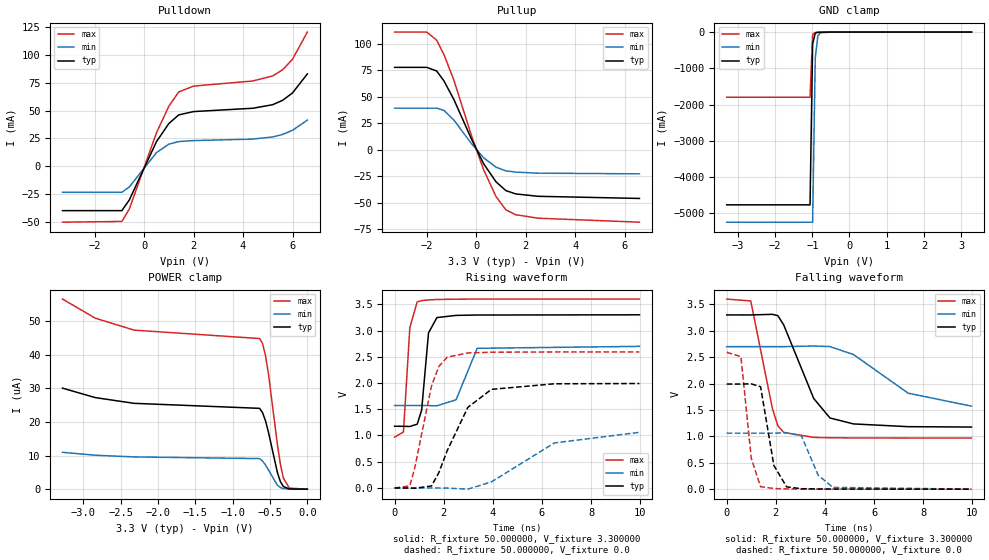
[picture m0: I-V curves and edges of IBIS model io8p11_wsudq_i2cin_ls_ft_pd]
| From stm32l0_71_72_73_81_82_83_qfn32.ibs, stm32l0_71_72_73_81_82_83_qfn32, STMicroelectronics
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|   Model io8p11_wsudq_i2cin_ls_ft_pd
[Model]  io8p11_wsudq_i2cin_ls_ft_pd
Model_type I/O
Polarity   Non-Inverting
Enable   Active-Low
Vinl =   0.990000V
Vinh =   2.310000V
Vmeas =  1.650000V
Cref =   50.000000pF
Rref =   100.000000M
Vref =   0.0V
C_comp   3.020400pF   2.988300pF   3.054500pF
[Temperature Range]   25.000000   0.125000k   -40.000000
[Pullup Reference]   3.300000V   2.700000V   3.600000V
[Pulldown Reference]   0.0V   0.0V   0.0V
[POWER Clamp Reference]   3.300000V   2.700000V   3.600000V
[GND Clamp Reference]   0.0V   0.0V   0.0V
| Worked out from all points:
|   slope of the pulldown table from 0 to 0.495 V, typ, clamps not added: 22.6 ohm
|   slope of the pullup table from 0 to 0.495 V, typ, clamps not added: 23.9 ohm
|   GND clamp passes 1 mA (typ) near -0.64 V on its own axis
|   rising waveform, R_fixture 50.000000, V_fixture 3.300000: 20-80 % time 225ps typ, 371ps min, 186ps max; typ from 1.18 V to 3.3 V
|   rising waveform, R_fixture 50.000000, V_fixture 0.0: 20-80 % time 1.18ns typ, 2.2ns min, 710ps max; typ from 0 V to 1.99 V
|   falling waveform, R_fixture 50.000000, V_fixture 3.300000: 20-80 % time 1.13ns typ, 2.09ns min, 655ps max; typ from 3.3 V to 1.18 V
|   falling waveform, R_fixture 50.000000, V_fixture 0.0: 20-80 % time 408ps typ, 574ps min, 329ps max; typ from 1.99 V to 0 V
[Pulldown]
|Voltage   I(typ)   I(min)   I(max)
-3.3V     -39.83mA   -23.37mA   -50.2mA
-900mV    -39.83mA   -23.37mA   -49.53mA
-600mV    -30.28mA   -18.59mA   -38.45mA
500mV     22.11mA    12.28mA    30.1mA
1V        38.33mA    19.81mA    53.88mA
1.4V      46.1mA     22.18mA    66.72mA
2V        49.07mA    23.02mA    71.93mA
4.4V      52.05mA    24.38mA    76.53mA
5.2V      55.25mA    26.3mA     81.02mA
5.6V      59.18mA    28.57mA    86.57mA
6V        65.79mA    32.24mA    95.97mA
6.6V      82.83mA    41.41mA    120.4mA
[Pullup]
|Voltage   I(typ)   I(min)   I(max)
-3.3V     77.63mA    39.16mA    110.9mA
-2V       77.63mA    39.16mA    110.9mA
-1.6V     74.23mA    39.16mA    103.3mA
-1.3V     64.67mA    36.99mA    89.45mA
-900mV    47.14mA    27.82mA    65.37mA
-200mV    10.4mA     5.949mA    13.84mA
300mV     -13.29mA   -7.65mA    -18.99mA
800mV     -30.32mA   -16.54mA   -44.19mA
1.2V      -38.62mA   -20mA      -56.79mA
1.6V      -41.75mA   -21.17mA   -61.39mA
2.5V      -43.99mA   -22.16mA   -64.64mA
6.6V      -46.01mA   -22.8mA    -68.41mA
[GND_clamp]
|Voltage   I(typ)   I(min)   I(max)
-3.3V     -4.766A    -5.244A    -1.797A
-1.06V    -4.766A    -5.244A    -1.797A
-990mV    -326.6mA   -5.244A    -67.91mA
-920mV    -28.93mA   -722.1mA   -10.97mA
-850mV    -6.625mA   -104.2mA   -6.541mA
-780mV    -3.477mA   -17.29mA   -4.218mA
-500mV    -68.5uA    -183uA     -41.48uA
3.28V     73.94uA    88.61uA    51.47uA
[POWER_clamp]
|Voltage   I(typ)   I(min)   I(max)
-3.28V    30.07uA    10.97uA    56.59uA
-2.84V    27.25uA    10.1uA     50.89uA
-2.32V    25.55uA    9.602uA    47.34uA
-640mV    24.06uA    9.099uA    44.84uA
-600mV    22.76uA    8.364uA    43.37uA
-560mV    20.32uA    7.211uA    39.74uA
-520mV    16.86uA    5.675uA    34.14uA
-400mV    4.841uA    1.145uA    13.1uA
-360mV    2.184uA    477.2nA    7.288uA
-320mV    772.4nA    180.3nA    3.213uA
-240mV    60.03nA    0A         295.3nA
0V        0A         0A         0A
[Ramp]
| variable   typ   min   max
dV/dt_r  1.19310/1.18050n   0.60954/2.07925n   1.55490/0.70842n
dV/dt_f  1.27158/1.13158n   0.59274/1.87936n   1.57816/0.65341n
R_load = 50.000000
[Rising Waveform]
R_fixture= 50.000000
V_fixture= 3.300000
V_fixture_min= 2.700000
V_fixture_max= 3.600000
|time   V(typ)   V(min)   V(max)
0s        1.176V     1.571V     967.8mV
360.4ps   1.175V     1.571V     1.067V
620.6ps   1.172V     1.571V     3.055V
920.9ps   1.216V     1.571V     3.545V
1.101ns   1.483V     1.571V     3.569V
1.381ns   2.954V     1.57V      3.583V
1.722ns   3.246V     1.566V     3.591V
2.503ns   3.288V     1.68V      3.597V
3.363ns   3.295V     2.661V     3.599V
9.97ns    3.299V     2.698V     3.599V
[Rising Waveform]
R_fixture= 50.000000
V_fixture= 0.0
V_fixture_min= 0.0
V_fixture_max= 0.0
|time   V(typ)   V(min)   V(max)
0s        -3.193uV   7.716uV    -219.6uV
620.6ps   -716.9uV   -7.893uV   40.33mV
820.8ps   -5.1mV     3.314uV    384.7mV
1.502ns   38.11mV    180.4uV    1.942V
1.802ns   292.1mV    -174uV     2.315V
2.142ns   711.3mV    -2.422mV   2.492V
2.983ns   1.536V     -22.39mV   2.573V
3.944ns   1.879V     116.5mV    2.587V
6.507ns   1.985V     857.8mV    2.591V
9.97ns    1.99V      1.06V      2.592V
[Falling Waveform]
R_fixture= 50.000000
V_fixture= 3.300000
V_fixture_min= 2.700000
V_fixture_max= 3.600000
|time   V(typ)   V(min)   V(max)
0s        3.299V     2.698V     3.599V
981ps     3.298V     2.698V     3.563V
1.862ns   3.31V      2.698V     1.525V
2.082ns   3.286V     2.698V     1.201V
2.322ns   3.11V      2.698V     1.074V
3.544ns   1.717V     2.71V      980.2mV
4.204ns   1.348V     2.699V     973.3mV
5.165ns   1.235V     2.549V     969.9mV
7.387ns   1.183V     1.818V     968.2mV
9.97ns    1.176V     1.571V     967.8mV
[Falling Waveform]
R_fixture= 50.000000
V_fixture= 0.0
V_fixture_min= 0.0
V_fixture_max= 0.0
|time   V(typ)   V(min)   V(max)
0s        1.99V      1.06V      2.592V
580.6ps   1.99V      1.06V      2.509V
1.001ns   1.994V     1.06V      584.3mV
1.381ns   1.938V     1.06V      46.33mV
1.922ns   448.1mV    1.06V      11.83mV
2.442ns   43.17mV    1.066V     4.743mV
3.043ns   8.498mV    1.01V      1.988mV
3.724ns   3.568mV    265.6mV    1.013mV
4.324ns   2.138mV    33.59mV    559.6uV
9.97ns    -3.193uV   7.716uV    -219.6uV
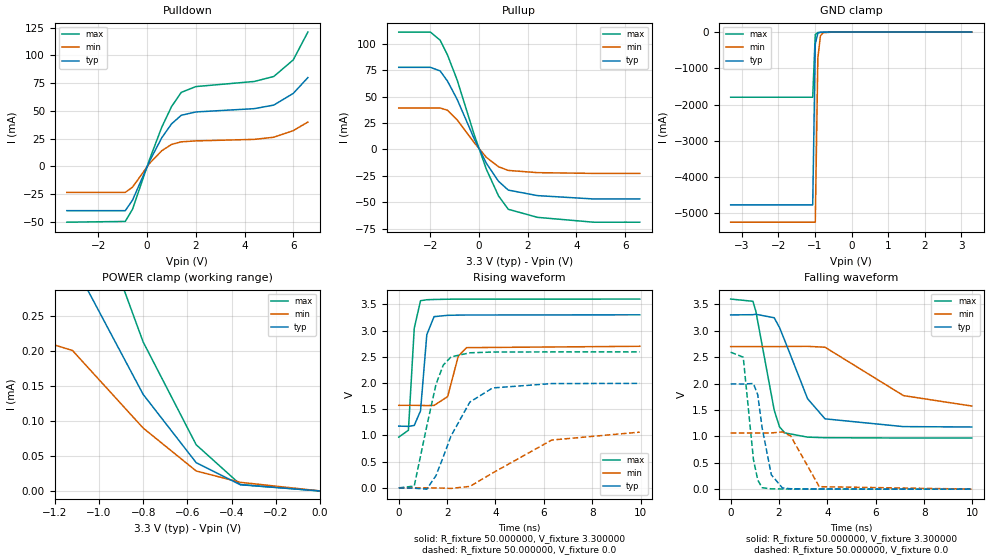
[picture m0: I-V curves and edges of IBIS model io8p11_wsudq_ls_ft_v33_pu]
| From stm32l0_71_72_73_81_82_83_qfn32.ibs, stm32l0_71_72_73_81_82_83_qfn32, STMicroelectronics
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|   Model io8p11_wsudq_ls_ft_v33_pu
[Model]  io8p11_wsudq_ls_ft_v33_pu
Model_type I/O
Polarity   Non-Inverting
Enable   Active-Low
Vinl =   0.990000V
Vinh =   2.310000V
Vmeas =  1.650000V
Cref =   50.000000pF
Rref =   100.000000M
Vref =   0.0V
C_comp   2.653200pF   2.620200pF   2.695100pF
[Temperature Range]   25.000000   0.125000k   -40.000000
[Pullup Reference]   3.300000V   2.700000V   3.600000V
[Pulldown Reference]   0.0V   0.0V   0.0V
[POWER Clamp Reference]   3.300000V   2.700000V   3.600000V
[GND Clamp Reference]   0.0V   0.0V   0.0V
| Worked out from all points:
|   slope of the pulldown table from 0 to 0.495 V, typ, clamps not added: 22.6 ohm
|   slope of the pullup table from 0 to 0.495 V, typ, clamps not added: 23.9 ohm
|   GND clamp passes 1 mA (typ) near -0.64 V on its own axis
|   POWER clamp passes 1 mA (typ) near -2.97 V on its own axis
|   rising waveform, R_fixture 50.000000, V_fixture 3.300000: 20-80 % time 215ps typ, 361ps min, 179ps max; typ from 1.18 V to 3.3 V
|   rising waveform, R_fixture 50.000000, V_fixture 0.0: 20-80 % time 1.18ns typ, 2.22ns min, 704ps max; typ from 0.001 V to 1.99 V
|   falling waveform, R_fixture 50.000000, V_fixture 3.300000: 20-80 % time 1.13ns typ, 2.11ns min, 645ps max; typ from 3.3 V to 1.18 V
|   falling waveform, R_fixture 50.000000, V_fixture 0.0: 20-80 % time 407ps typ, 577ps min, 327ps max; typ from 1.99 V to 0.001 V
[Pulldown]
|Voltage   I(typ)   I(min)   I(max)
-3.3V     -39.83mA   -23.37mA   -50.2mA
-900mV    -39.83mA   -23.37mA   -49.52mA
-600mV    -30.28mA   -18.59mA   -38.45mA
100mV     4.867mA    2.821mA    6.48mA
600mV     25.85mA    14.17mA    35.39mA
1V        38.33mA    19.81mA    53.88mA
1.4V      46.1mA     22.18mA    66.72mA
2V        49.07mA    23.02mA    71.93mA
4.4V      52.05mA    24.38mA    76.53mA
5.2V      55.25mA    26.31mA    81.02mA
6V        65.78mA    32.24mA    95.96mA
6.6V      80mA       40mA       121mA
[Pullup]
|Voltage   I(typ)   I(min)   I(max)
-3.3V     77.64mA    39.15mA    111mA
-2V       77.64mA    39.15mA    111mA
-1.6V     74.25mA    39.15mA    103.3mA
-1.3V     64.67mA    37mA       89.48mA
-900mV    47.28mA    27.9mA     65.58mA
-200mV    9.95mA     6.235mA    13.84mA
300mV     -13.29mA   -7.65mA    -18.99mA
800mV     -30.32mA   -16.54mA   -44.19mA
1.2V      -38.62mA   -19.99mA   -56.79mA
2.4V      -43.84mA   -22.09mA   -64.42mA
4.7V      -47mA      -22.8mA    -69mA
6.6V      -47mA      -22.8mA    -69mA
[GND_clamp]
|Voltage   I(typ)   I(min)   I(max)
-3.3V     -4.766A    -5.244A    -1.797A
-1.06V    -4.766A    -5.244A    -1.797A
-990mV    -326.7mA   -5.244A    -68.05mA
-920mV    -29.09mA   -722.2mA   -11.16mA
-850mV    -6.797mA   -104.4mA   -6.682mA
-780mV    -3.554mA   -17.44mA   -4.265mA
-500mV    -58.08uA   -169.3uA   -34.1uA
3.28V     0A         0A         0A
[POWER_clamp]
|Voltage   I(typ)   I(min)   I(max)
-3.28V    3.05A      226.6uA    3.724A
-2.96V    694.9uA    211.8uA    3.724A
-2.92V    479.6uA    211.8uA    509.1mA
-2.88V    432uA      211.8uA    70.08mA
-2.76V    412.8uA    211.8uA    794.1uA
-1.32V    411.6uA    211.8uA    593.3uA
-1.24V    395.5uA    211.8uA    578.2uA
-1.12V    327.2uA    200.2uA    487.6uA
-800mV    137.6uA    89.62uA    212.3uA
-560mV    40.27uA    28.42uA    65.81uA
-360mV    8.799uA    12.27uA    9.112uA
0V        0A         0A         0A
[Ramp]
| variable   typ   min   max
dV/dt_r  1.19474/1.17894n   0.62717/2.19037n   1.55541/0.70304n
dV/dt_f  1.27254/1.12625n   0.63192/2.02257n   1.57813/0.64401n
R_load = 50.000000
[Rising Waveform]
R_fixture= 50.000000
V_fixture= 3.300000
V_fixture_min= 2.700000
V_fixture_max= 3.600000
|time   V(typ)   V(min)   V(max)
0s        1.178V     1.575V     969.1mV
400.4ps   1.174V     1.575V     1.099V
640.6ps   1.191V     1.575V     3.042V
900.9ps   1.469V     1.573V     3.569V
1.161ns   2.923V     1.57V      3.587V
1.461ns   3.265V     1.573V     3.592V
2.022ns   3.29V      1.74V      3.597V
2.462ns   3.294V     2.511V     3.599V
2.803ns   3.296V     2.674V     3.599V
9.97ns    3.3V       2.7V       3.6V
[Rising Waveform]
R_fixture= 50.000000
V_fixture= 0.0
V_fixture_min= 0.0
V_fixture_max= 0.0
|time   V(typ)   V(min)   V(max)
0s        1.292mV    1.83mV     669uV
640.6ps   -4.514mV   2.016mV    36.15mV
1.161ns   -23.33mV   1.831mV    1.18V
1.542ns   237.1mV    -132.9uV   1.978V
1.842ns   592.8mV    -3.605mV   2.341V
2.162ns   991mV      -9.027mV   2.498V
2.943ns   1.638V     29.39mV    2.576V
3.884ns   1.906V     285.4mV    2.59V
6.326ns   1.989V     912.9mV    2.593V
9.97ns    1.993V     1.064V     2.593V
[Falling Waveform]
R_fixture= 50.000000
V_fixture= 3.300000
V_fixture_min= 2.700000
V_fixture_max= 3.600000
|time   V(typ)   V(min)   V(max)
0s        3.3V       2.7V       3.6V
920.9ps   3.304V     2.7V       3.558V
1.041ns   3.312V     2.7V       3.37V
1.802ns   3.246V     2.7V       1.495V
2.022ns   3.059V     2.699V     1.179V
2.242ns   2.811V     2.702V     1.066V
3.183ns   1.712V     2.705V     985.6mV
3.904ns   1.332V     2.688V     975mV
7.147ns   1.185V     1.772V     969.2mV
9.97ns    1.178V     1.575V     969.1mV
[Falling Waveform]
R_fixture= 50.000000
V_fixture= 0.0
V_fixture_min= 0.0
V_fixture_max= 0.0
|time   V(typ)   V(min)   V(max)
0s        1.993V     1.064V     2.593V
520.5ps   1.992V     1.064V     2.5V
940.9ps   2.001V     1.064V     566.3mV
1.121ns   1.786V     1.064V     172.9mV
1.301ns   1.163V     1.064V     27.77mV
1.682ns   272.6mV    1.065V     6.697mV
2.142ns   23.78mV    1.084V     4.495mV
2.482ns   8.347mV    1.008V     3.402mV
3.664ns   3.755mV    47.72mV    1.398mV
9.97ns    1.292mV    1.83mV     669uV
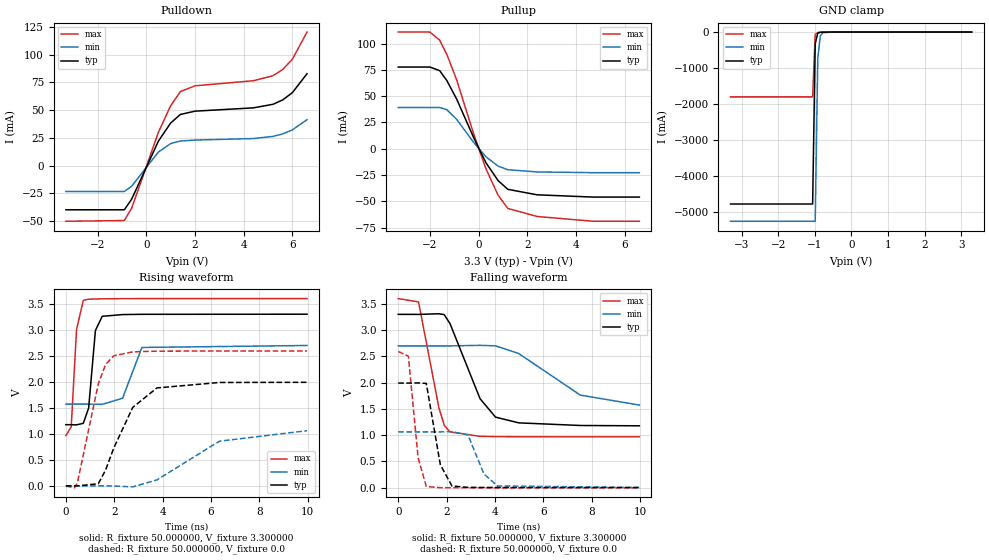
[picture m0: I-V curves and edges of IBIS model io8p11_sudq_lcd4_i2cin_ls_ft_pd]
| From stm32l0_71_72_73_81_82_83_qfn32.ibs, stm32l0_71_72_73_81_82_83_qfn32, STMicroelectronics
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|   Model io8p11_sudq_lcd4_i2cin_ls_ft_pd
[Model]  io8p11_sudq_lcd4_i2cin_ls_ft_pd
Model_type I/O
Polarity   Non-Inverting
Enable   Active-Low
Vinl =   0.990000V
Vinh =   2.310000V
Vmeas =  1.650000V
Cref =   50.000000pF
Rref =   100.000000M
Vref =   0.0V
C_comp   2.499500pF   2.460800pF   2.557800pF
[Temperature Range]   25.000000   0.125000k   -40.000000
[Pullup Reference]   3.300000V   2.700000V   3.600000V
[Pulldown Reference]   0.0V   0.0V   0.0V
[POWER Clamp Reference]   3.300000V   2.700000V   3.600000V
[GND Clamp Reference]   0.0V   0.0V   0.0V
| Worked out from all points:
|   slope of the pulldown table from 0 to 0.495 V, typ, clamps not added: 22.6 ohm
|   slope of the pullup table from 0 to 0.495 V, typ, clamps not added: 23.9 ohm
|   GND clamp passes 1 mA (typ) near -0.64 V on its own axis
|   rising waveform, R_fixture 50.000000, V_fixture 3.300000: 20-80 % time 218ps typ, 365ps min, 178ps max; typ from 1.18 V to 3.3 V
|   rising waveform, R_fixture 50.000000, V_fixture 0.0: 20-80 % time 1.18ns typ, 2.21ns min, 705ps max; typ from 0 V to 1.99 V
|   falling waveform, R_fixture 50.000000, V_fixture 3.300000: 20-80 % time 1.11ns typ, 2.11ns min, 638ps max; typ from 3.3 V to 1.18 V
|   falling waveform, R_fixture 50.000000, V_fixture 0.0: 20-80 % time 385ps typ, 555ps min, 307ps max; typ from 1.99 V to 0 V
[Pulldown]
|Voltage   I(typ)   I(min)   I(max)
-3.3V     -39.83mA   -23.36mA   -50.2mA
-900mV    -39.83mA   -23.36mA   -49.53mA
-600mV    -30.28mA   -18.59mA   -38.45mA
500mV     22.11mA    12.28mA    30.1mA
1V        38.33mA    19.81mA    53.88mA
1.4V      46.1mA     22.18mA    66.72mA
2V        49.07mA    23.02mA    71.93mA
4.4V      52.05mA    24.38mA    76.53mA
5.2V      55.25mA    26.31mA    81.02mA
5.6V      59.18mA    28.57mA    86.57mA
6V        65.78mA    32.24mA    95.96mA
6.6V      82.83mA    41.41mA    120.4mA
[Pullup]
|Voltage   I(typ)   I(min)   I(max)
-3.3V     77.64mA    39.16mA    110.9mA
-2V       77.64mA    39.16mA    110.9mA
-1.6V     74.23mA    39.16mA    103.2mA
-1.3V     64.67mA    36.99mA    89.45mA
-900mV    47.14mA    27.82mA    65.37mA
-200mV    10.4mA     5.949mA    13.84mA
300mV     -13.29mA   -7.65mA    -18.99mA
800mV     -30.32mA   -16.54mA   -44.19mA
1.2V      -38.62mA   -20mA      -56.79mA
2.4V      -43.84mA   -22.09mA   -64.42mA
4.7V      -46mA      -22.8mA    -69mA
6.6V      -46mA      -22.8mA    -69mA
[GND_clamp]
|Voltage   I(typ)   I(min)   I(max)
-3.3V     -4.766A    -5.244A    -1.797A
-1.06V    -4.766A    -5.244A    -1.797A
-990mV    -326.4mA   -5.244A    -67.86mA
-920mV    -28.84mA   -721.7mA   -11.09mA
-850mV    -6.698mA   -104.1mA   -6.716mA
-780mV    -3.564mA   -17.3mA    -4.334mA
-500mV    -70.03uA   -187.2uA   -42.37uA
3.28V     73.94uA    88.61uA    51.47uA
[POWER_clamp]
|Voltage   I(typ)   I(min)   I(max)
-3.28V    0A         0A         0A
0V        0A         0A         0A
[Ramp]
| variable   typ   min   max
dV/dt_r  1.19370/1.17451n   0.61068/2.08309n   1.55514/0.70192n
dV/dt_f  1.27212/1.10990n   0.59526/1.87208n   1.57831/0.63688n
R_load = 50.000000
[Rising Waveform]
R_fixture= 50.000000
V_fixture= 3.300000
V_fixture_min= 2.700000
V_fixture_max= 3.600000
|time   V(typ)   V(min)   V(max)
0s        1.176V     1.571V     966mV
220.2ps   1.175V     1.571V     1.134V
440.4ps   1.172V     1.571V     3.004V
720.7ps   1.202V     1.571V     3.566V
940.9ps   1.496V     1.571V     3.587V
1.221ns   2.986V     1.57V      3.592V
1.502ns   3.259V     1.567V     3.595V
2.342ns   3.292V     1.683V     3.598V
3.143ns   3.297V     2.66V      3.599V
9.97ns    3.299V     2.698V     3.599V
[Rising Waveform]
R_fixture= 50.000000
V_fixture= 0.0
V_fixture_min= 0.0
V_fixture_max= 0.0
|time   V(typ)   V(min)   V(max)
0s        169.8uV    8.29uV     -5.703mV
360.4ps   25.93uV    -4.447uV   -38.06mV
480.5ps   -1.029mV   -7.957uV   68.46mV
1.341ns   41.36mV    180.2uV    1.962V
1.642ns   304mV      -187uV     2.333V
1.982ns   729.4mV    -2.481mV   2.5V
2.763ns   1.507V     -19.44mV   2.576V
3.764ns   1.882V     114.5mV    2.589V
6.346ns   1.987V     858.2mV    2.592V
9.97ns    1.99V      1.06V      2.592V
[Falling Waveform]
R_fixture= 50.000000
V_fixture= 3.300000
V_fixture_min= 2.700000
V_fixture_max= 3.600000
|time   V(typ)   V(min)   V(max)
0s        3.299V     2.698V     3.599V
840.8ps   3.298V     2.698V     3.536V
1.682ns   3.31V      2.698V     1.519V
1.902ns   3.294V     2.698V     1.186V
2.142ns   3.122V     2.698V     1.059V
3.383ns   1.692V     2.709V     975.5mV
4.024ns   1.341V     2.699V     969.9mV
4.985ns   1.232V     2.552V     967.2mV
7.528ns   1.182V     1.761V     966.1mV
9.97ns    1.176V     1.571V     966mV
[Falling Waveform]
R_fixture= 50.000000
V_fixture= 0.0
V_fixture_min= 0.0
V_fixture_max= 0.0
|time   V(typ)   V(min)   V(max)
0s        1.99V      1.06V      2.592V
420.4ps   1.99V      1.06V      2.502V
820.8ps   1.993V     1.06V      570mV
1.161ns   1.983V     1.06V      20.47mV
1.742ns   434mV      1.06V      -2.996mV
2.222ns   29.07mV    1.064V     -3.939mV
2.883ns   3.211mV    1.003V     -4.778mV
3.544ns   2.016mV    258.7mV    -5.258mV
4.104ns   1.429mV    30.53mV    -5.469mV
9.97ns    169.8uV    8.29uV     -5.703mV
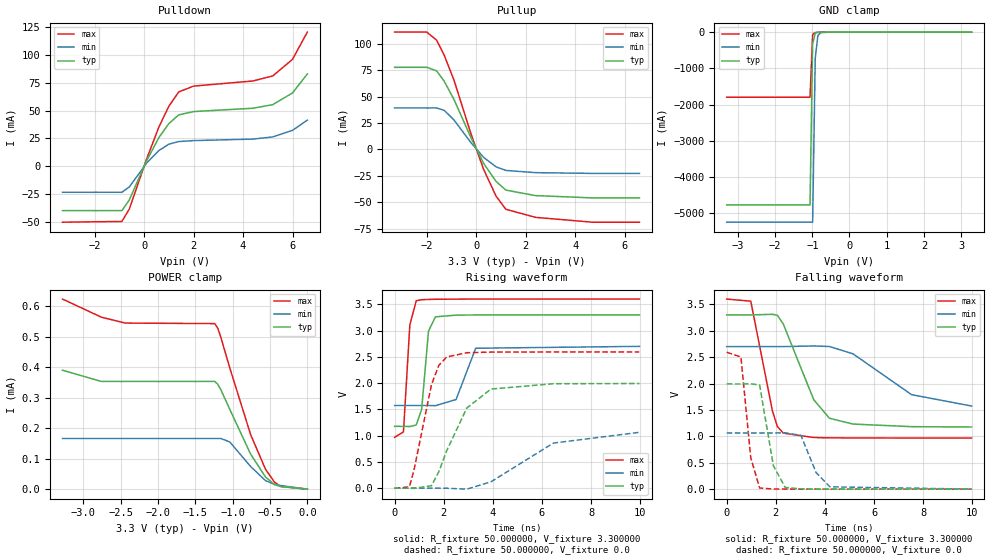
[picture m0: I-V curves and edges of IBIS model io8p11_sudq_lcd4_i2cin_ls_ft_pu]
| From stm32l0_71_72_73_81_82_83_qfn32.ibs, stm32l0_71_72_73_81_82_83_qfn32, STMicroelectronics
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|   Model io8p11_sudq_lcd4_i2cin_ls_ft_pu
[Model]  io8p11_sudq_lcd4_i2cin_ls_ft_pu
Model_type I/O
Polarity   Non-Inverting
Enable   Active-Low
Vinl =   0.990000V
Vinh =   2.310000V
Vmeas =  1.650000V
Cref =   50.000000pF
Rref =   100.000000M
Vref =   0.0V
C_comp   2.499500pF   2.460800pF   2.557800pF
[Temperature Range]   25.000000   0.125000k   -40.000000
[Pullup Reference]   3.300000V   2.700000V   3.600000V
[Pulldown Reference]   0.0V   0.0V   0.0V
[POWER Clamp Reference]   3.300000V   2.700000V   3.600000V
[GND Clamp Reference]   0.0V   0.0V   0.0V
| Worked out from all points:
|   slope of the pulldown table from 0 to 0.495 V, typ, clamps not added: 22.6 ohm
|   slope of the pullup table from 0 to 0.495 V, typ, clamps not added: 23.9 ohm
|   GND clamp passes 1 mA (typ) near -0.64 V on its own axis
|   rising waveform, R_fixture 50.000000, V_fixture 3.300000: 20-80 % time 217ps typ, 364ps min, 177ps max; typ from 1.18 V to 3.3 V
|   rising waveform, R_fixture 50.000000, V_fixture 0.0: 20-80 % time 1.18ns typ, 2.2ns min, 703ps max; typ from 0.001 V to 1.99 V
|   falling waveform, R_fixture 50.000000, V_fixture 3.300000: 20-80 % time 1.11ns typ, 2.04ns min, 635ps max; typ from 3.3 V to 1.18 V
|   falling waveform, R_fixture 50.000000, V_fixture 0.0: 20-80 % time 391ps typ, 562ps min, 314ps max; typ from 1.99 V to 0.001 V
[Pulldown]
|Voltage   I(typ)   I(min)   I(max)
-3.3V     -39.83mA   -23.36mA   -50.2mA
-900mV    -39.83mA   -23.36mA   -49.52mA
-600mV    -30.28mA   -18.59mA   -38.45mA
100mV     4.867mA    2.821mA    6.48mA
600mV     25.85mA    14.17mA    35.39mA
1V        38.33mA    19.81mA    53.88mA
1.4V      46.1mA     22.18mA    66.72mA
2V        49.07mA    23.02mA    71.93mA
4.4V      52.05mA    24.38mA    76.53mA
5.2V      55.25mA    26.31mA    81.02mA
6V        65.79mA    32.24mA    95.96mA
6.6V      82.83mA    41.41mA    120.4mA
[Pullup]
|Voltage   I(typ)   I(min)   I(max)
-3.3V     77.64mA    39.15mA    111mA
-2V       77.64mA    39.15mA    111mA
-1.6V     74.25mA    39.15mA    103.3mA
-1.3V     64.67mA    37mA       89.48mA
-900mV    47.24mA    27.86mA    65.53mA
-200mV    10.44mA    5.971mA    13.84mA
300mV     -13.29mA   -7.65mA    -18.99mA
800mV     -30.32mA   -16.54mA   -44.19mA
1.2V      -38.62mA   -20mA      -56.79mA
2.4V      -43.84mA   -22.09mA   -64.42mA
4.7V      -46mA      -22.8mA    -69mA
6.6V      -46mA      -22.8mA    -69mA
[GND_clamp]
|Voltage   I(typ)   I(min)   I(max)
-3.3V     -4.766A    -5.244A    -1.797A
-1.06V    -4.766A    -5.244A    -1.797A
-990mV    -326.4mA   -5.244A    -67.85mA
-920mV    -28.83mA   -721.7mA   -11.08mA
-850mV    -6.686mA   -104.1mA   -6.707mA
-780mV    -3.552mA   -17.28mA   -4.326mA
-500mV    -59.41uA   -172uA     -34.91uA
3.28V     0A         0A         0A
[POWER_clamp]
|Voltage   I(typ)   I(min)   I(max)
-3.28V    390.5uA    166.4uA    624.1uA
-2.76V    353.6uA    166.4uA    564.7uA
-2.44V    353.6uA    166.4uA    545.3uA
-1.24V    353.6uA    166.4uA    543.5uA
-1.2V     344.2uA    166.4uA    528.2uA
-1.16V    327.1uA    166.4uA    499.5uA
-1.04V    262.6uA    155.2uA    398.8uA
-760mV    115.1uA    74.4uA     179.3uA
-560mV    39.87uA    27.94uA    65.07uA
-440mV    15uA       15.53uA    23.15uA
-360mV    8.745uA    12.05uA    9.091uA
0V        0A         0A         0A
[Ramp]
| variable   typ   min   max
dV/dt_r  1.19456/1.17840n   0.61241/2.08906n   1.55541/0.70198n
dV/dt_f  1.27170/1.10858n   0.59334/1.82473n   1.57812/0.63446n
R_load = 50.000000
[Rising Waveform]
R_fixture= 50.000000
V_fixture= 3.300000
V_fixture_min= 2.700000
V_fixture_max= 3.600000
|time   V(typ)   V(min)   V(max)
0s        1.178V     1.575V     968.7mV
360.4ps   1.177V     1.575V     1.072V
620.6ps   1.174V     1.575V     3.107V
880.9ps   1.204V     1.575V     3.568V
1.101ns   1.5V       1.575V     3.588V
1.381ns   2.991V     1.574V     3.593V
1.662ns   3.262V     1.571V     3.596V
2.503ns   3.294V     1.688V     3.599V
3.303ns   3.298V     2.664V     3.6V
9.97ns    3.3V       2.7V       3.6V
[Rising Waveform]
R_fixture= 50.000000
V_fixture= 0.0
V_fixture_min= 0.0
V_fixture_max= 0.0
|time   V(typ)   V(min)   V(max)
0s        1.058mV    1.824mV    416.4uV
600.6ps   539uV      1.81mV     24.81mV
780.8ps   -2.931mV   1.817mV    325.4mV
1.502ns   47.41mV    1.995mV    1.972V
1.802ns   315.2mV    1.629mV    2.339V
2.122ns   714.4mV    -437.1uV   2.498V
2.943ns   1.528V     -17.85mV   2.579V
3.924ns   1.887V     122.5mV    2.591V
6.466ns   1.989V     859.1mV    2.593V
9.97ns    1.993V     1.064V     2.593V
[Falling Waveform]
R_fixture= 50.000000
V_fixture= 3.300000
V_fixture_min= 2.700000
V_fixture_max= 3.600000
|time   V(typ)   V(min)   V(max)
0s        3.3V       2.7V       3.6V
981ps     3.3V       2.7V       3.56V
1.862ns   3.311V     2.7V       1.484V
2.062ns   3.294V     2.7V       1.189V
2.302ns   3.131V     2.7V       1.062V
3.544ns   1.695V     2.712V     978.2mV
4.184ns   1.343V     2.702V     972.6mV
5.145ns   1.233V     2.563V     969.9mV
7.528ns   1.184V     1.79V      968.8mV
9.97ns    1.178V     1.575V     968.7mV
[Falling Waveform]
R_fixture= 50.000000
V_fixture= 0.0
V_fixture_min= 0.0
V_fixture_max= 0.0
|time   V(typ)   V(min)   V(max)
0s        1.993V     1.064V     2.593V
580.6ps   1.992V     1.064V     2.503V
981ps     1.996V     1.064V     593.5mV
1.341ns   1.972V     1.064V     23.05mV
1.902ns   444.1mV    1.064V     3.192mV
2.382ns   33.51mV    1.068V     2.199mV
3.023ns   4.544mV    1.019V     1.363mV
3.644ns   3.132mV    311.9mV    893.6uV
4.204ns   2.448mV    44.5mV     668uV
9.97ns    1.058mV    1.824mV    416.4uV
